VERSION 5.7 ;
  NOWIREEXTENSIONATPIN ON ;
  DIVIDERCHAR "/" ;
  BUSBITCHARS "[]" ;
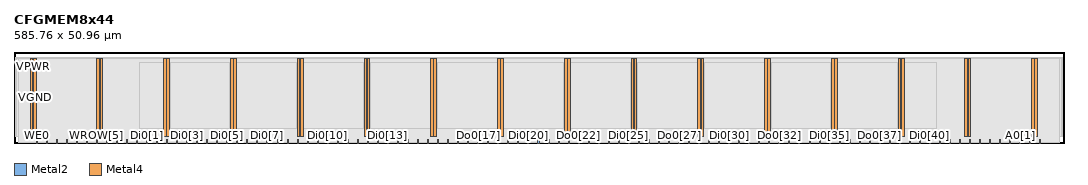
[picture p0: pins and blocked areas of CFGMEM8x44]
MACRO CFGMEM8x44
  CLASS BLOCK ;
  FOREIGN CFGMEM8x44 ;
  ORIGIN 0.000 0.000 ;
  SIZE 585.760 BY 50.960 ;
  PIN A0[0]
    DIRECTION INPUT ;
    USE SIGNAL ;
    ANTENNAGATEAREA 0.726000 ;
    ANTENNADIFFAREA 0.410400 ;
    PORT
      LAYER Metal2 ;
        RECT 555.520 0.000 556.080 2.000 ;
    END
  END A0[0]
  PIN A0[1]
    DIRECTION INPUT ;
    USE SIGNAL ;
    ANTENNAGATEAREA 0.726000 ;
    ANTENNADIFFAREA 0.410400 ;
    PORT
      LAYER Metal2 ;
        RECT 561.120 0.000 561.680 2.000 ;
    END
  END A0[1]
  PIN A0[2]
    DIRECTION INPUT ;
    USE SIGNAL ;
    ANTENNAGATEAREA 0.726000 ;
    ANTENNADIFFAREA 0.410400 ;
    PORT
      LAYER Metal2 ;
        RECT 566.720 0.000 567.280 2.000 ;
    END
  END A0[2]
  PIN Di0[0]
    DIRECTION INPUT ;
    USE SIGNAL ;
    ANTENNAGATEAREA 0.552000 ;
    PORT
      LAYER Metal2 ;
        RECT 62.720 0.000 63.280 2.000 ;
    END
  END Di0[0]
  PIN Di0[10]
    DIRECTION INPUT ;
    USE SIGNAL ;
    ANTENNAGATEAREA 0.552000 ;
    PORT
      LAYER Metal2 ;
        RECT 174.720 0.000 175.280 2.000 ;
    END
  END Di0[10]
  PIN Di0[11]
    DIRECTION INPUT ;
    USE SIGNAL ;
    ANTENNAGATEAREA 0.552000 ;
    PORT
      LAYER Metal2 ;
        RECT 185.920 0.000 186.480 2.000 ;
    END
  END Di0[11]
  PIN Di0[12]
    DIRECTION INPUT ;
    USE SIGNAL ;
    ANTENNAGATEAREA 0.552000 ;
    PORT
      LAYER Metal2 ;
        RECT 197.120 0.000 197.680 2.000 ;
    END
  END Di0[12]
  PIN Di0[13]
    DIRECTION INPUT ;
    USE SIGNAL ;
    ANTENNAGATEAREA 0.552000 ;
    PORT
      LAYER Metal2 ;
        RECT 208.320 0.000 208.880 2.000 ;
    END
  END Di0[13]
  PIN Di0[14]
    DIRECTION INPUT ;
    USE SIGNAL ;
    ANTENNAGATEAREA 0.552000 ;
    PORT
      LAYER Metal2 ;
        RECT 219.520 0.000 220.080 2.000 ;
    END
  END Di0[14]
  PIN Di0[15]
    DIRECTION INPUT ;
    USE SIGNAL ;
    ANTENNAGATEAREA 0.552000 ;
    PORT
      LAYER Metal2 ;
        RECT 230.720 0.000 231.280 2.000 ;
    END
  END Di0[15]
  PIN Di0[16]
    DIRECTION INPUT ;
    USE SIGNAL ;
    ANTENNAGATEAREA 0.552000 ;
    PORT
      LAYER Metal2 ;
        RECT 241.920 0.000 242.480 2.000 ;
    END
  END Di0[16]
  PIN Di0[17]
    DIRECTION INPUT ;
    USE SIGNAL ;
    ANTENNAGATEAREA 0.552000 ;
    PORT
      LAYER Metal2 ;
        RECT 253.120 0.000 253.680 2.000 ;
    END
  END Di0[17]
  PIN Di0[18]
    DIRECTION INPUT ;
    USE SIGNAL ;
    ANTENNAGATEAREA 0.552000 ;
    PORT
      LAYER Metal2 ;
        RECT 264.320 0.000 264.880 2.000 ;
    END
  END Di0[18]
  PIN Di0[19]
    DIRECTION INPUT ;
    USE SIGNAL ;
    ANTENNAGATEAREA 0.552000 ;
    PORT
      LAYER Metal2 ;
        RECT 275.520 0.000 276.080 2.000 ;
    END
  END Di0[19]
  PIN Di0[1]
    DIRECTION INPUT ;
    USE SIGNAL ;
    ANTENNAGATEAREA 0.552000 ;
    PORT
      LAYER Metal2 ;
        RECT 73.920 0.000 74.480 2.000 ;
    END
  END Di0[1]
  PIN Di0[20]
    DIRECTION INPUT ;
    USE SIGNAL ;
    ANTENNAGATEAREA 0.552000 ;
    PORT
      LAYER Metal2 ;
        RECT 286.720 0.000 287.280 2.000 ;
    END
  END Di0[20]
  PIN Di0[21]
    DIRECTION INPUT ;
    USE SIGNAL ;
    ANTENNAGATEAREA 0.552000 ;
    PORT
      LAYER Metal2 ;
        RECT 297.920 0.000 298.480 2.000 ;
    END
  END Di0[21]
  PIN Di0[22]
    DIRECTION INPUT ;
    USE SIGNAL ;
    ANTENNAGATEAREA 0.552000 ;
    PORT
      LAYER Metal2 ;
        RECT 309.120 0.000 309.680 2.000 ;
    END
  END Di0[22]
  PIN Di0[23]
    DIRECTION INPUT ;
    USE SIGNAL ;
    ANTENNAGATEAREA 0.552000 ;
    PORT
      LAYER Metal2 ;
        RECT 320.320 0.000 320.880 2.000 ;
    END
  END Di0[23]
  PIN Di0[24]
    DIRECTION INPUT ;
    USE SIGNAL ;
    ANTENNAGATEAREA 0.552000 ;
    PORT
      LAYER Metal2 ;
        RECT 331.520 0.000 332.080 2.000 ;
    END
  END Di0[24]
  PIN Di0[25]
    DIRECTION INPUT ;
    USE SIGNAL ;
    ANTENNAGATEAREA 0.552000 ;
    PORT
      LAYER Metal2 ;
        RECT 342.720 0.000 343.280 2.000 ;
    END
  END Di0[25]
  PIN Di0[26]
    DIRECTION INPUT ;
    USE SIGNAL ;
    ANTENNAGATEAREA 0.552000 ;
    PORT
      LAYER Metal2 ;
        RECT 353.920 0.000 354.480 2.000 ;
    END
  END Di0[26]
  PIN Di0[27]
    DIRECTION INPUT ;
    USE SIGNAL ;
    ANTENNAGATEAREA 0.552000 ;
    PORT
      LAYER Metal2 ;
        RECT 365.120 0.000 365.680 2.000 ;
    END
  END Di0[27]
  PIN Di0[28]
    DIRECTION INPUT ;
    USE SIGNAL ;
    ANTENNAGATEAREA 0.552000 ;
    PORT
      LAYER Metal2 ;
        RECT 376.320 0.000 376.880 2.000 ;
    END
  END Di0[28]
  PIN Di0[29]
    DIRECTION INPUT ;
    USE SIGNAL ;
    ANTENNAGATEAREA 0.552000 ;
    PORT
      LAYER Metal2 ;
        RECT 387.520 0.000 388.080 2.000 ;
    END
  END Di0[29]
  PIN Di0[2]
    DIRECTION INPUT ;
    USE SIGNAL ;
    ANTENNAGATEAREA 0.552000 ;
    PORT
      LAYER Metal2 ;
        RECT 85.120 0.000 85.680 2.000 ;
    END
  END Di0[2]
  PIN Di0[30]
    DIRECTION INPUT ;
    USE SIGNAL ;
    ANTENNAGATEAREA 0.552000 ;
    PORT
      LAYER Metal2 ;
        RECT 398.720 0.000 399.280 2.000 ;
    END
  END Di0[30]
  PIN Di0[31]
    DIRECTION INPUT ;
    USE SIGNAL ;
    ANTENNAGATEAREA 0.552000 ;
    PORT
      LAYER Metal2 ;
        RECT 409.920 0.000 410.480 2.000 ;
    END
  END Di0[31]
  PIN Di0[32]
    DIRECTION INPUT ;
    USE SIGNAL ;
    ANTENNAGATEAREA 0.552000 ;
    PORT
      LAYER Metal2 ;
        RECT 421.120 0.000 421.680 2.000 ;
    END
  END Di0[32]
  PIN Di0[33]
    DIRECTION INPUT ;
    USE SIGNAL ;
    ANTENNAGATEAREA 0.552000 ;
    PORT
      LAYER Metal2 ;
        RECT 432.320 0.000 432.880 2.000 ;
    END
  END Di0[33]
  PIN Di0[34]
    DIRECTION INPUT ;
    USE SIGNAL ;
    ANTENNAGATEAREA 0.552000 ;
    PORT
      LAYER Metal2 ;
        RECT 443.520 0.000 444.080 2.000 ;
    END
  END Di0[34]
  PIN Di0[35]
    DIRECTION INPUT ;
    USE SIGNAL ;
    ANTENNAGATEAREA 0.552000 ;
    PORT
      LAYER Metal2 ;
        RECT 454.720 0.000 455.280 2.000 ;
    END
  END Di0[35]
  PIN Di0[36]
    DIRECTION INPUT ;
    USE SIGNAL ;
    ANTENNAGATEAREA 0.552000 ;
    PORT
      LAYER Metal2 ;
        RECT 465.920 0.000 466.480 2.000 ;
    END
  END Di0[36]
  PIN Di0[37]
    DIRECTION INPUT ;
    USE SIGNAL ;
    ANTENNAGATEAREA 0.552000 ;
    PORT
      LAYER Metal2 ;
        RECT 477.120 0.000 477.680 2.000 ;
    END
  END Di0[37]
  PIN Di0[38]
    DIRECTION INPUT ;
    USE SIGNAL ;
    ANTENNAGATEAREA 0.552000 ;
    PORT
      LAYER Metal2 ;
        RECT 488.320 0.000 488.880 2.000 ;
    END
  END Di0[38]
  PIN Di0[39]
    DIRECTION INPUT ;
    USE SIGNAL ;
    ANTENNAGATEAREA 0.552000 ;
    PORT
      LAYER Metal2 ;
        RECT 499.520 0.000 500.080 2.000 ;
    END
  END Di0[39]
  PIN Di0[3]
    DIRECTION INPUT ;
    USE SIGNAL ;
    ANTENNAGATEAREA 0.552000 ;
    PORT
      LAYER Metal2 ;
        RECT 96.320 0.000 96.880 2.000 ;
    END
  END Di0[3]
  PIN Di0[40]
    DIRECTION INPUT ;
    USE SIGNAL ;
    ANTENNAGATEAREA 0.552000 ;
    PORT
      LAYER Metal2 ;
        RECT 510.720 0.000 511.280 2.000 ;
    END
  END Di0[40]
  PIN Di0[41]
    DIRECTION INPUT ;
    USE SIGNAL ;
    ANTENNAGATEAREA 0.552000 ;
    PORT
      LAYER Metal2 ;
        RECT 521.920 0.000 522.480 2.000 ;
    END
  END Di0[41]
  PIN Di0[42]
    DIRECTION INPUT ;
    USE SIGNAL ;
    ANTENNAGATEAREA 0.552000 ;
    PORT
      LAYER Metal2 ;
        RECT 533.120 0.000 533.680 2.000 ;
    END
  END Di0[42]
  PIN Di0[43]
    DIRECTION INPUT ;
    USE SIGNAL ;
    ANTENNAGATEAREA 0.552000 ;
    PORT
      LAYER Metal2 ;
        RECT 544.320 0.000 544.880 2.000 ;
    END
  END Di0[43]
  PIN Di0[4]
    DIRECTION INPUT ;
    USE SIGNAL ;
    ANTENNAGATEAREA 0.552000 ;
    PORT
      LAYER Metal2 ;
        RECT 107.520 0.000 108.080 2.000 ;
    END
  END Di0[4]
  PIN Di0[5]
    DIRECTION INPUT ;
    USE SIGNAL ;
    ANTENNAGATEAREA 0.552000 ;
    PORT
      LAYER Metal2 ;
        RECT 118.720 0.000 119.280 2.000 ;
    END
  END Di0[5]
  PIN Di0[6]
    DIRECTION INPUT ;
    USE SIGNAL ;
    ANTENNAGATEAREA 0.552000 ;
    PORT
      LAYER Metal2 ;
        RECT 129.920 0.000 130.480 2.000 ;
    END
  END Di0[6]
  PIN Di0[7]
    DIRECTION INPUT ;
    USE SIGNAL ;
    ANTENNAGATEAREA 0.552000 ;
    PORT
      LAYER Metal2 ;
        RECT 141.120 0.000 141.680 2.000 ;
    END
  END Di0[7]
  PIN Di0[8]
    DIRECTION INPUT ;
    USE SIGNAL ;
    ANTENNAGATEAREA 0.552000 ;
    PORT
      LAYER Metal2 ;
        RECT 152.320 0.000 152.880 2.000 ;
    END
  END Di0[8]
  PIN Di0[9]
    DIRECTION INPUT ;
    USE SIGNAL ;
    ANTENNAGATEAREA 0.552000 ;
    PORT
      LAYER Metal2 ;
        RECT 163.520 0.000 164.080 2.000 ;
    END
  END Di0[9]
  PIN Do0[0]
    DIRECTION OUTPUT ;
    USE SIGNAL ;
    ANTENNADIFFAREA 1.239600 ;
    PORT
      LAYER Metal2 ;
        RECT 68.320 0.000 68.880 2.000 ;
    END
  END Do0[0]
  PIN Do0[10]
    DIRECTION OUTPUT ;
    USE SIGNAL ;
    ANTENNADIFFAREA 1.239600 ;
    PORT
      LAYER Metal2 ;
        RECT 180.320 0.000 180.880 2.000 ;
    END
  END Do0[10]
  PIN Do0[11]
    DIRECTION OUTPUT ;
    USE SIGNAL ;
    ANTENNADIFFAREA 1.239600 ;
    PORT
      LAYER Metal2 ;
        RECT 191.520 0.000 192.080 2.000 ;
    END
  END Do0[11]
  PIN Do0[12]
    DIRECTION OUTPUT ;
    USE SIGNAL ;
    ANTENNADIFFAREA 1.239600 ;
    PORT
      LAYER Metal2 ;
        RECT 202.720 0.000 203.280 2.000 ;
    END
  END Do0[12]
  PIN Do0[13]
    DIRECTION OUTPUT ;
    USE SIGNAL ;
    ANTENNADIFFAREA 1.239600 ;
    PORT
      LAYER Metal2 ;
        RECT 213.920 0.000 214.480 2.000 ;
    END
  END Do0[13]
  PIN Do0[14]
    DIRECTION OUTPUT ;
    USE SIGNAL ;
    ANTENNADIFFAREA 1.239600 ;
    PORT
      LAYER Metal2 ;
        RECT 225.120 0.000 225.680 2.000 ;
    END
  END Do0[14]
  PIN Do0[15]
    DIRECTION OUTPUT ;
    USE SIGNAL ;
    ANTENNADIFFAREA 1.239600 ;
    PORT
      LAYER Metal2 ;
        RECT 236.320 0.000 236.880 2.000 ;
    END
  END Do0[15]
  PIN Do0[16]
    DIRECTION OUTPUT ;
    USE SIGNAL ;
    ANTENNADIFFAREA 1.239600 ;
    PORT
      LAYER Metal2 ;
        RECT 247.520 0.000 248.080 2.000 ;
    END
  END Do0[16]
  PIN Do0[17]
    DIRECTION OUTPUT ;
    USE SIGNAL ;
    ANTENNADIFFAREA 1.239600 ;
    PORT
      LAYER Metal2 ;
        RECT 258.720 0.000 259.280 2.000 ;
    END
  END Do0[17]
  PIN Do0[18]
    DIRECTION OUTPUT ;
    USE SIGNAL ;
    ANTENNADIFFAREA 1.239600 ;
    PORT
      LAYER Metal2 ;
        RECT 269.920 0.000 270.480 2.000 ;
    END
  END Do0[18]
  PIN Do0[19]
    DIRECTION OUTPUT ;
    USE SIGNAL ;
    ANTENNADIFFAREA 1.239600 ;
    PORT
      LAYER Metal2 ;
        RECT 281.120 0.000 281.680 2.000 ;
    END
  END Do0[19]
  PIN Do0[1]
    DIRECTION OUTPUT ;
    USE SIGNAL ;
    ANTENNADIFFAREA 1.239600 ;
    PORT
      LAYER Metal2 ;
        RECT 79.520 0.000 80.080 2.000 ;
    END
  END Do0[1]
  PIN Do0[20]
    DIRECTION OUTPUT ;
    USE SIGNAL ;
    ANTENNADIFFAREA 1.239600 ;
    PORT
      LAYER Metal2 ;
        RECT 292.320 0.000 292.880 2.000 ;
    END
  END Do0[20]
  PIN Do0[21]
    DIRECTION OUTPUT ;
    USE SIGNAL ;
    ANTENNADIFFAREA 1.239600 ;
    PORT
      LAYER Metal2 ;
        RECT 303.520 0.000 304.080 2.000 ;
    END
  END Do0[21]
  PIN Do0[22]
    DIRECTION OUTPUT ;
    USE SIGNAL ;
    ANTENNADIFFAREA 1.239600 ;
    PORT
      LAYER Metal2 ;
        RECT 314.720 0.000 315.280 2.000 ;
    END
  END Do0[22]
  PIN Do0[23]
    DIRECTION OUTPUT ;
    USE SIGNAL ;
    ANTENNADIFFAREA 1.239600 ;
    PORT
      LAYER Metal2 ;
        RECT 325.920 0.000 326.480 2.000 ;
    END
  END Do0[23]
  PIN Do0[24]
    DIRECTION OUTPUT ;
    USE SIGNAL ;
    ANTENNADIFFAREA 1.239600 ;
    PORT
      LAYER Metal2 ;
        RECT 337.120 0.000 337.680 2.000 ;
    END
  END Do0[24]
  PIN Do0[25]
    DIRECTION OUTPUT ;
    USE SIGNAL ;
    ANTENNADIFFAREA 1.239600 ;
    PORT
      LAYER Metal2 ;
        RECT 348.320 0.000 348.880 2.000 ;
    END
  END Do0[25]
  PIN Do0[26]
    DIRECTION OUTPUT ;
    USE SIGNAL ;
    ANTENNADIFFAREA 1.239600 ;
    PORT
      LAYER Metal2 ;
        RECT 359.520 0.000 360.080 2.000 ;
    END
  END Do0[26]
  PIN Do0[27]
    DIRECTION OUTPUT ;
    USE SIGNAL ;
    ANTENNADIFFAREA 1.239600 ;
    PORT
      LAYER Metal2 ;
        RECT 370.720 0.000 371.280 2.000 ;
    END
  END Do0[27]
  PIN Do0[28]
    DIRECTION OUTPUT ;
    USE SIGNAL ;
    ANTENNADIFFAREA 1.239600 ;
    PORT
      LAYER Metal2 ;
        RECT 381.920 0.000 382.480 2.000 ;
    END
  END Do0[28]
  PIN Do0[29]
    DIRECTION OUTPUT ;
    USE SIGNAL ;
    ANTENNADIFFAREA 1.239600 ;
    PORT
      LAYER Metal2 ;
        RECT 393.120 0.000 393.680 2.000 ;
    END
  END Do0[29]
  PIN Do0[2]
    DIRECTION OUTPUT ;
    USE SIGNAL ;
    ANTENNADIFFAREA 1.239600 ;
    PORT
      LAYER Metal2 ;
        RECT 90.720 0.000 91.280 2.000 ;
    END
  END Do0[2]
  PIN Do0[30]
    DIRECTION OUTPUT ;
    USE SIGNAL ;
    ANTENNADIFFAREA 1.239600 ;
    PORT
      LAYER Metal2 ;
        RECT 404.320 0.000 404.880 2.000 ;
    END
  END Do0[30]
  PIN Do0[31]
    DIRECTION OUTPUT ;
    USE SIGNAL ;
    ANTENNADIFFAREA 1.239600 ;
    PORT
      LAYER Metal2 ;
        RECT 415.520 0.000 416.080 2.000 ;
    END
  END Do0[31]
  PIN Do0[32]
    DIRECTION OUTPUT ;
    USE SIGNAL ;
    ANTENNADIFFAREA 1.239600 ;
    PORT
      LAYER Metal2 ;
        RECT 426.720 0.000 427.280 2.000 ;
    END
  END Do0[32]
  PIN Do0[33]
    DIRECTION OUTPUT ;
    USE SIGNAL ;
    ANTENNADIFFAREA 1.239600 ;
    PORT
      LAYER Metal2 ;
        RECT 437.920 0.000 438.480 2.000 ;
    END
  END Do0[33]
  PIN Do0[34]
    DIRECTION OUTPUT ;
    USE SIGNAL ;
    ANTENNADIFFAREA 1.239600 ;
    PORT
      LAYER Metal2 ;
        RECT 449.120 0.000 449.680 2.000 ;
    END
  END Do0[34]
  PIN Do0[35]
    DIRECTION OUTPUT ;
    USE SIGNAL ;
    ANTENNADIFFAREA 1.239600 ;
    PORT
      LAYER Metal2 ;
        RECT 460.320 0.000 460.880 2.000 ;
    END
  END Do0[35]
  PIN Do0[36]
    DIRECTION OUTPUT ;
    USE SIGNAL ;
    ANTENNADIFFAREA 1.239600 ;
    PORT
      LAYER Metal2 ;
        RECT 471.520 0.000 472.080 2.000 ;
    END
  END Do0[36]
  PIN Do0[37]
    DIRECTION OUTPUT ;
    USE SIGNAL ;
    ANTENNADIFFAREA 1.239600 ;
    PORT
      LAYER Metal2 ;
        RECT 482.720 0.000 483.280 2.000 ;
    END
  END Do0[37]
  PIN Do0[38]
    DIRECTION OUTPUT ;
    USE SIGNAL ;
    ANTENNADIFFAREA 1.239600 ;
    PORT
      LAYER Metal2 ;
        RECT 493.920 0.000 494.480 2.000 ;
    END
  END Do0[38]
  PIN Do0[39]
    DIRECTION OUTPUT ;
    USE SIGNAL ;
    ANTENNADIFFAREA 1.239600 ;
    PORT
      LAYER Metal2 ;
        RECT 505.120 0.000 505.680 2.000 ;
    END
  END Do0[39]
  PIN Do0[3]
    DIRECTION OUTPUT ;
    USE SIGNAL ;
    ANTENNADIFFAREA 1.239600 ;
    PORT
      LAYER Metal2 ;
        RECT 101.920 0.000 102.480 2.000 ;
    END
  END Do0[3]
  PIN Do0[40]
    DIRECTION OUTPUT ;
    USE SIGNAL ;
    ANTENNADIFFAREA 1.239600 ;
    PORT
      LAYER Metal2 ;
        RECT 516.320 0.000 516.880 2.000 ;
    END
  END Do0[40]
  PIN Do0[41]
    DIRECTION OUTPUT ;
    USE SIGNAL ;
    ANTENNADIFFAREA 1.239600 ;
    PORT
      LAYER Metal2 ;
        RECT 527.520 0.000 528.080 2.000 ;
    END
  END Do0[41]
  PIN Do0[42]
    DIRECTION OUTPUT ;
    USE SIGNAL ;
    ANTENNADIFFAREA 1.239600 ;
    PORT
      LAYER Metal2 ;
        RECT 538.720 0.000 539.280 2.000 ;
    END
  END Do0[42]
  PIN Do0[43]
    DIRECTION OUTPUT ;
    USE SIGNAL ;
    ANTENNADIFFAREA 1.239600 ;
    PORT
      LAYER Metal2 ;
        RECT 549.920 0.000 550.480 2.000 ;
    END
  END Do0[43]
  PIN Do0[4]
    DIRECTION OUTPUT ;
    USE SIGNAL ;
    ANTENNADIFFAREA 1.239600 ;
    PORT
      LAYER Metal2 ;
        RECT 113.120 0.000 113.680 2.000 ;
    END
  END Do0[4]
  PIN Do0[5]
    DIRECTION OUTPUT ;
    USE SIGNAL ;
    ANTENNADIFFAREA 1.239600 ;
    PORT
      LAYER Metal2 ;
        RECT 124.320 0.000 124.880 2.000 ;
    END
  END Do0[5]
  PIN Do0[6]
    DIRECTION OUTPUT ;
    USE SIGNAL ;
    ANTENNADIFFAREA 1.239600 ;
    PORT
      LAYER Metal2 ;
        RECT 135.520 0.000 136.080 2.000 ;
    END
  END Do0[6]
  PIN Do0[7]
    DIRECTION OUTPUT ;
    USE SIGNAL ;
    ANTENNADIFFAREA 1.239600 ;
    PORT
      LAYER Metal2 ;
        RECT 146.720 0.000 147.280 2.000 ;
    END
  END Do0[7]
  PIN Do0[8]
    DIRECTION OUTPUT ;
    USE SIGNAL ;
    ANTENNADIFFAREA 1.239600 ;
    PORT
      LAYER Metal2 ;
        RECT 157.920 0.000 158.480 2.000 ;
    END
  END Do0[8]
  PIN Do0[9]
    DIRECTION OUTPUT ;
    USE SIGNAL ;
    ANTENNADIFFAREA 1.239600 ;
    PORT
      LAYER Metal2 ;
        RECT 169.120 0.000 169.680 2.000 ;
    END
  END Do0[9]
  PIN EN0
    DIRECTION INPUT ;
    USE SIGNAL ;
    ANTENNAGATEAREA 0.726000 ;
    ANTENNADIFFAREA 0.410400 ;
    PORT
      LAYER Metal2 ;
        RECT 572.320 0.000 572.880 2.000 ;
    END
  END EN0
  PIN VGND
    DIRECTION INOUT ;
    USE GROUND ;
    PORT
      LAYER Metal4 ;
        RECT 10.800 3.620 12.300 47.340 ;
    END
    PORT
      LAYER Metal4 ;
        RECT 48.050 3.620 49.550 47.340 ;
    END
    PORT
      LAYER Metal4 ;
        RECT 85.300 3.620 86.800 47.340 ;
    END
    PORT
      LAYER Metal4 ;
        RECT 122.550 3.620 124.050 47.340 ;
    END
    PORT
      LAYER Metal4 ;
        RECT 159.800 3.620 161.300 47.340 ;
    END
    PORT
      LAYER Metal4 ;
        RECT 197.050 3.620 198.550 47.340 ;
    END
    PORT
      LAYER Metal4 ;
        RECT 234.300 3.620 235.800 47.340 ;
    END
    PORT
      LAYER Metal4 ;
        RECT 271.550 3.620 273.050 47.340 ;
    END
    PORT
      LAYER Metal4 ;
        RECT 308.800 3.620 310.300 47.340 ;
    END
    PORT
      LAYER Metal4 ;
        RECT 346.050 3.620 347.550 47.340 ;
    END
    PORT
      LAYER Metal4 ;
        RECT 383.300 3.620 384.800 47.340 ;
    END
    PORT
      LAYER Metal4 ;
        RECT 420.550 3.620 422.050 47.340 ;
    END
    PORT
      LAYER Metal4 ;
        RECT 457.800 3.620 459.300 47.340 ;
    END
    PORT
      LAYER Metal4 ;
        RECT 495.050 3.620 496.550 47.340 ;
    END
    PORT
      LAYER Metal4 ;
        RECT 532.300 3.620 533.800 47.340 ;
    END
    PORT
      LAYER Metal4 ;
        RECT 569.550 3.620 571.050 47.340 ;
    END
  END VGND
  PIN VPWR
    DIRECTION INOUT ;
    USE POWER ;
    PORT
      LAYER Metal4 ;
        RECT 9.020 3.620 10.520 47.340 ;
    END
    PORT
      LAYER Metal4 ;
        RECT 46.270 3.620 47.770 47.340 ;
    END
    PORT
      LAYER Metal4 ;
        RECT 83.520 3.620 85.020 47.340 ;
    END
    PORT
      LAYER Metal4 ;
        RECT 120.770 3.620 122.270 47.340 ;
    END
    PORT
      LAYER Metal4 ;
        RECT 158.020 3.620 159.520 47.340 ;
    END
    PORT
      LAYER Metal4 ;
        RECT 195.270 3.620 196.770 47.340 ;
    END
    PORT
      LAYER Metal4 ;
        RECT 232.520 3.620 234.020 47.340 ;
    END
    PORT
      LAYER Metal4 ;
        RECT 269.770 3.620 271.270 47.340 ;
    END
    PORT
      LAYER Metal4 ;
        RECT 307.020 3.620 308.520 47.340 ;
    END
    PORT
      LAYER Metal4 ;
        RECT 344.270 3.620 345.770 47.340 ;
    END
    PORT
      LAYER Metal4 ;
        RECT 381.520 3.620 383.020 47.340 ;
    END
    PORT
      LAYER Metal4 ;
        RECT 418.770 3.620 420.270 47.340 ;
    END
    PORT
      LAYER Metal4 ;
        RECT 456.020 3.620 457.520 47.340 ;
    END
    PORT
      LAYER Metal4 ;
        RECT 493.270 3.620 494.770 47.340 ;
    END
    PORT
      LAYER Metal4 ;
        RECT 530.520 3.620 532.020 47.340 ;
    END
    PORT
      LAYER Metal4 ;
        RECT 567.770 3.620 569.270 47.340 ;
    END
  END VPWR
  PIN WE0
    DIRECTION INPUT ;
    USE SIGNAL ;
    ANTENNAGATEAREA 16.440001 ;
    ANTENNADIFFAREA 0.410400 ;
    PORT
      LAYER Metal2 ;
        RECT 12.320 0.000 12.880 2.000 ;
    END
  END WE0
  PIN WROW[0]
    DIRECTION INPUT ;
    USE SIGNAL ;
    ANTENNAGATEAREA 2.055000 ;
    PORT
      LAYER Metal2 ;
        RECT 17.920 0.000 18.480 2.000 ;
    END
  END WROW[0]
  PIN WROW[1]
    DIRECTION INPUT ;
    USE SIGNAL ;
    ANTENNAGATEAREA 2.055000 ;
    PORT
      LAYER Metal2 ;
        RECT 23.520 0.000 24.080 2.000 ;
    END
  END WROW[1]
  PIN WROW[2]
    DIRECTION INPUT ;
    USE SIGNAL ;
    ANTENNAGATEAREA 2.055000 ;
    PORT
      LAYER Metal2 ;
        RECT 29.120 0.000 29.680 2.000 ;
    END
  END WROW[2]
  PIN WROW[3]
    DIRECTION INPUT ;
    USE SIGNAL ;
    ANTENNAGATEAREA 2.055000 ;
    PORT
      LAYER Metal2 ;
        RECT 34.720 0.000 35.280 2.000 ;
    END
  END WROW[3]
  PIN WROW[4]
    DIRECTION INPUT ;
    USE SIGNAL ;
    ANTENNAGATEAREA 2.055000 ;
    PORT
      LAYER Metal2 ;
        RECT 40.320 0.000 40.880 2.000 ;
    END
  END WROW[4]
  PIN WROW[5]
    DIRECTION INPUT ;
    USE SIGNAL ;
    ANTENNAGATEAREA 2.055000 ;
    PORT
      LAYER Metal2 ;
        RECT 45.920 0.000 46.480 2.000 ;
    END
  END WROW[5]
  PIN WROW[6]
    DIRECTION INPUT ;
    USE SIGNAL ;
    ANTENNAGATEAREA 2.055000 ;
    PORT
      LAYER Metal2 ;
        RECT 51.520 0.000 52.080 2.000 ;
    END
  END WROW[6]
  PIN WROW[7]
    DIRECTION INPUT ;
    USE SIGNAL ;
    ANTENNAGATEAREA 2.055000 ;
    PORT
      LAYER Metal2 ;
        RECT 57.120 0.000 57.680 2.000 ;
    END
  END WROW[7]
  OBS
      LAYER Nwell ;
        RECT 0.690 44.880 585.070 47.470 ;
      LAYER Pwell ;
        RECT 0.690 41.360 585.070 44.880 ;
      LAYER Nwell ;
        RECT 0.690 37.040 585.070 41.360 ;
      LAYER Pwell ;
        RECT 0.690 33.520 585.070 37.040 ;
      LAYER Nwell ;
        RECT 0.690 29.200 585.070 33.520 ;
      LAYER Pwell ;
        RECT 0.690 25.680 585.070 29.200 ;
      LAYER Nwell ;
        RECT 0.690 21.360 585.070 25.680 ;
      LAYER Pwell ;
        RECT 0.690 17.840 585.070 21.360 ;
      LAYER Nwell ;
        RECT 0.690 13.520 585.070 17.840 ;
      LAYER Pwell ;
        RECT 0.690 10.000 585.070 13.520 ;
      LAYER Nwell ;
        RECT 0.690 5.680 585.070 10.000 ;
      LAYER Pwell ;
        RECT 0.690 3.490 585.070 5.680 ;
      LAYER Metal1 ;
        RECT 1.120 3.620 584.640 47.340 ;
      LAYER Metal2 ;
        RECT 2.380 2.300 583.380 47.230 ;
        RECT 2.380 0.090 12.020 2.300 ;
        RECT 13.180 0.090 17.620 2.300 ;
        RECT 18.780 0.090 23.220 2.300 ;
        RECT 24.380 0.090 28.820 2.300 ;
        RECT 29.980 0.090 34.420 2.300 ;
        RECT 35.580 0.090 40.020 2.300 ;
        RECT 41.180 0.090 45.620 2.300 ;
        RECT 46.780 0.090 51.220 2.300 ;
        RECT 52.380 0.090 56.820 2.300 ;
        RECT 57.980 0.090 62.420 2.300 ;
        RECT 63.580 0.090 68.020 2.300 ;
        RECT 69.180 0.090 73.620 2.300 ;
        RECT 74.780 0.090 79.220 2.300 ;
        RECT 80.380 0.090 84.820 2.300 ;
        RECT 85.980 0.090 90.420 2.300 ;
        RECT 91.580 0.090 96.020 2.300 ;
        RECT 97.180 0.090 101.620 2.300 ;
        RECT 102.780 0.090 107.220 2.300 ;
        RECT 108.380 0.090 112.820 2.300 ;
        RECT 113.980 0.090 118.420 2.300 ;
        RECT 119.580 0.090 124.020 2.300 ;
        RECT 125.180 0.090 129.620 2.300 ;
        RECT 130.780 0.090 135.220 2.300 ;
        RECT 136.380 0.090 140.820 2.300 ;
        RECT 141.980 0.090 146.420 2.300 ;
        RECT 147.580 0.090 152.020 2.300 ;
        RECT 153.180 0.090 157.620 2.300 ;
        RECT 158.780 0.090 163.220 2.300 ;
        RECT 164.380 0.090 168.820 2.300 ;
        RECT 169.980 0.090 174.420 2.300 ;
        RECT 175.580 0.090 180.020 2.300 ;
        RECT 181.180 0.090 185.620 2.300 ;
        RECT 186.780 0.090 191.220 2.300 ;
        RECT 192.380 0.090 196.820 2.300 ;
        RECT 197.980 0.090 202.420 2.300 ;
        RECT 203.580 0.090 208.020 2.300 ;
        RECT 209.180 0.090 213.620 2.300 ;
        RECT 214.780 0.090 219.220 2.300 ;
        RECT 220.380 0.090 224.820 2.300 ;
        RECT 225.980 0.090 230.420 2.300 ;
        RECT 231.580 0.090 236.020 2.300 ;
        RECT 237.180 0.090 241.620 2.300 ;
        RECT 242.780 0.090 247.220 2.300 ;
        RECT 248.380 0.090 252.820 2.300 ;
        RECT 253.980 0.090 258.420 2.300 ;
        RECT 259.580 0.090 264.020 2.300 ;
        RECT 265.180 0.090 269.620 2.300 ;
        RECT 270.780 0.090 275.220 2.300 ;
        RECT 276.380 0.090 280.820 2.300 ;
        RECT 281.980 0.090 286.420 2.300 ;
        RECT 287.580 0.090 292.020 2.300 ;
        RECT 293.180 0.090 297.620 2.300 ;
        RECT 298.780 0.090 303.220 2.300 ;
        RECT 304.380 0.090 308.820 2.300 ;
        RECT 309.980 0.090 314.420 2.300 ;
        RECT 315.580 0.090 320.020 2.300 ;
        RECT 321.180 0.090 325.620 2.300 ;
        RECT 326.780 0.090 331.220 2.300 ;
        RECT 332.380 0.090 336.820 2.300 ;
        RECT 337.980 0.090 342.420 2.300 ;
        RECT 343.580 0.090 348.020 2.300 ;
        RECT 349.180 0.090 353.620 2.300 ;
        RECT 354.780 0.090 359.220 2.300 ;
        RECT 360.380 0.090 364.820 2.300 ;
        RECT 365.980 0.090 370.420 2.300 ;
        RECT 371.580 0.090 376.020 2.300 ;
        RECT 377.180 0.090 381.620 2.300 ;
        RECT 382.780 0.090 387.220 2.300 ;
        RECT 388.380 0.090 392.820 2.300 ;
        RECT 393.980 0.090 398.420 2.300 ;
        RECT 399.580 0.090 404.020 2.300 ;
        RECT 405.180 0.090 409.620 2.300 ;
        RECT 410.780 0.090 415.220 2.300 ;
        RECT 416.380 0.090 420.820 2.300 ;
        RECT 421.980 0.090 426.420 2.300 ;
        RECT 427.580 0.090 432.020 2.300 ;
        RECT 433.180 0.090 437.620 2.300 ;
        RECT 438.780 0.090 443.220 2.300 ;
        RECT 444.380 0.090 448.820 2.300 ;
        RECT 449.980 0.090 454.420 2.300 ;
        RECT 455.580 0.090 460.020 2.300 ;
        RECT 461.180 0.090 465.620 2.300 ;
        RECT 466.780 0.090 471.220 2.300 ;
        RECT 472.380 0.090 476.820 2.300 ;
        RECT 477.980 0.090 482.420 2.300 ;
        RECT 483.580 0.090 488.020 2.300 ;
        RECT 489.180 0.090 493.620 2.300 ;
        RECT 494.780 0.090 499.220 2.300 ;
        RECT 500.380 0.090 504.820 2.300 ;
        RECT 505.980 0.090 510.420 2.300 ;
        RECT 511.580 0.090 516.020 2.300 ;
        RECT 517.180 0.090 521.620 2.300 ;
        RECT 522.780 0.090 527.220 2.300 ;
        RECT 528.380 0.090 532.820 2.300 ;
        RECT 533.980 0.090 538.420 2.300 ;
        RECT 539.580 0.090 544.020 2.300 ;
        RECT 545.180 0.090 549.620 2.300 ;
        RECT 550.780 0.090 555.220 2.300 ;
        RECT 556.380 0.090 560.820 2.300 ;
        RECT 561.980 0.090 566.420 2.300 ;
        RECT 567.580 0.090 572.020 2.300 ;
        RECT 573.180 0.090 583.380 2.300 ;
      LAYER Metal3 ;
        RECT 2.330 0.140 583.430 47.180 ;
      LAYER Metal4 ;
        RECT 70.140 7.930 83.220 44.710 ;
        RECT 87.100 7.930 120.470 44.710 ;
        RECT 124.350 7.930 157.720 44.710 ;
        RECT 161.600 7.930 194.970 44.710 ;
        RECT 198.850 7.930 232.220 44.710 ;
        RECT 236.100 7.930 269.470 44.710 ;
        RECT 273.350 7.930 306.720 44.710 ;
        RECT 310.600 7.930 343.970 44.710 ;
        RECT 347.850 7.930 381.220 44.710 ;
        RECT 385.100 7.930 418.470 44.710 ;
        RECT 422.350 7.930 455.720 44.710 ;
        RECT 459.600 7.930 492.970 44.710 ;
        RECT 496.850 7.930 514.500 44.710 ;
  END
END CFGMEM8x44
END LIBRARY

